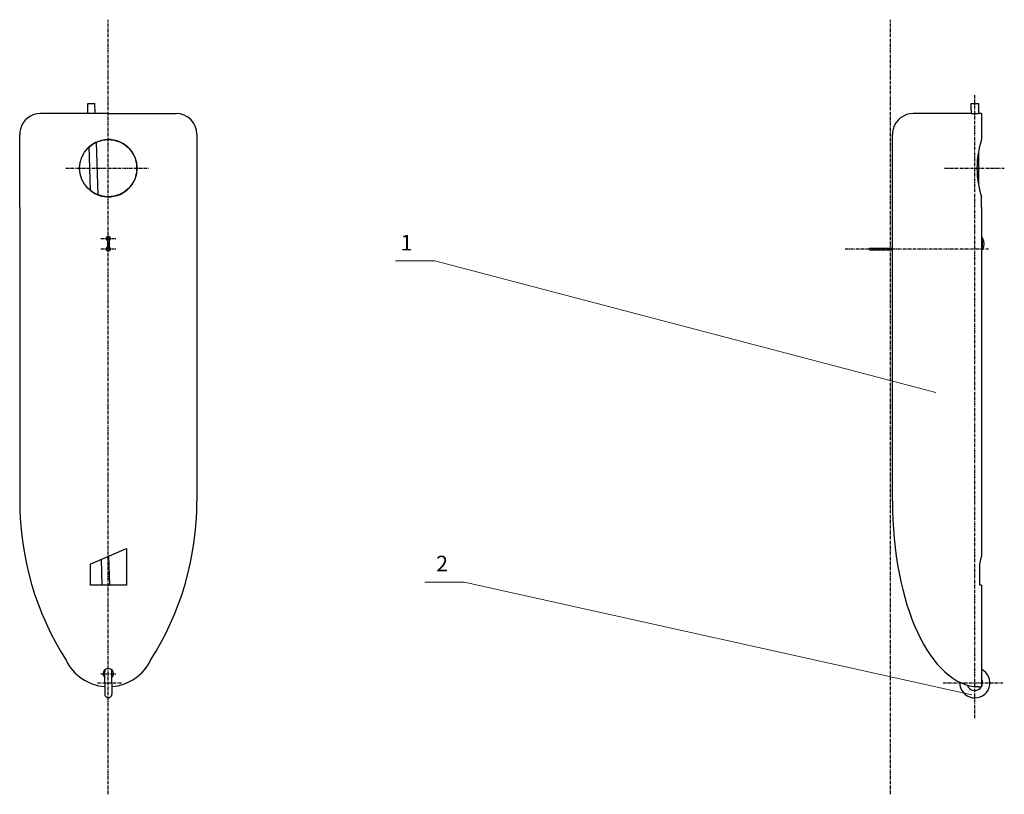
# Model space of a CAD drawing. Units: millimetres. Extents: x -17 to 172, y 40 to 189.
import ezdxf

# ---------------------------------------------------------------- set-up
doc = ezdxf.new("R2010")
doc.units = ezdxf.units.MM
doc.header["$LTSCALE"] = 0.2
doc.linetypes.add('ACAD_ISO10W100', pattern=[18, 12, -3, 0, -3])

msp = doc.modelspace()

# ---------------------------------------------------------------- linework, layer by layer
at = {"color": 1, "linetype": 'ACAD_ISO10W100', "lineweight": 25, "ltscale": 0.25}
for p, q in [((0, 114.83), (0, 189.15)), ((150, 114.83), (150, 189.15)), ((166.2, 55.09), (166.2, 174.77)), ((-8.12, 160.65), (7.88, 160.65)), ((160.36, 160.65), (171.86, 160.65)), ((-1.42, 147.15), (1.52, 147.15)), ((-1.42, 145.15), (1.52, 145.15)), ((141.36, 145.15), (168.85, 145.15)), ((0, 40.5), (0, 114.83)), ((150, 40.5), (150, 114.83)), ((-1.42, 63.65), (1.52, 63.65)), ((-2.08, 61.9), (2.53, 61.9)), ((160.1, 61.9), (171.6, 61.9))]:
    msp.add_line(p, q, dxfattribs=at)
at = {"color": 7, "lineweight": 30, "ltscale": 0.25}
for p, q in [((-3.9, 171.15), (-3.96, 173.05)), ((-3.96, 173.05), (-2.56, 173.05)), ((-2.5, 171.15), (-2.56, 173.05)), ((165.5, 173.05), (166.9, 173.05)), ((165.5, 171.85), (165.5, 173.05)), ((166.9, 173.05), (166.9, 171.15)), ((0, 171.15), (-13, 171.15)), ((0, 171.15), (13, 171.15)), ((165.5, 171.15), (154.4, 171.15)), ((165.5, 171.85), (165.5, 171.15)), ((165.5, 171.15), (166.9, 171.15)), ((167.5, 171.15), (166.9, 171.15)), ((167.5, 171.15), (167.5, 168.15)), ((167.5, 168.15), (167.5, 166.15)), ((-17, 153.15), (-17, 167.15)), ((17, 167.15), (17, 96.76)), ((150.4, 153.15), (150.4, 167.15)), ((-3.71, 164.89), (-3.46, 156.38)), ((-2.33, 165.63), (-2.03, 155.54)), ((166.9, 163.81), (166.9, 157.5)), ((167.5, 153.15), (167.5, 155.15)), ((-17, 153.15), (-17, 96.76)), ((150.4, 96.78), (150.4, 153.15)), ((167.5, 153.15), (167.5, 86.15)), ((-0.15, 147.15), (-0.15, 145.15)), ((0.15, 147.15), (0.15, 145.15)), ((146, 145.3), (150.4, 145.3)), ((146, 145.3), (146, 145)), ((146, 145), (150.4, 145)), ((-3.5, 84.65), (3.5, 87.65)), ((3.5, 87.65), (3.5, 80.65)), ((-1.19, 80.65), (-1.34, 85.58)), ((0.04, 86.17), (0.21, 80.65)), ((167.14, 84.65), (167.5, 86.15)), ((-3.5, 84.65), (-3.5, 80.65)), ((167.14, 80.65), (167.14, 84.65)), ((3.5, 80.65), (-3.5, 80.65)), ((167.5, 80.65), (167.14, 80.65)), ((167.5, 80.65), (167.5, 61.15)), ((-0.7, 61.9), (-0.7, 64.11)), ((0.7, 61.9), (0.7, 64.1)), ((-0.7, 61.9), (-0.7, 59.75)), ((0.7, 61.9), (0.7, 59.75)), ((166.9, 61.15), (167.5, 61.15))]:
    msp.add_line(p, q, dxfattribs=at)
at = {"color": 7, "lineweight": 15, "ltscale": 0.25}
for p, q in [((62.6, 142.89), (55.06, 142.89)), ((158.7, 117.64), (62.6, 142.89)), ((68.27, 81.22), (60.72, 81.22)), ((165.63, 59.56), (68.27, 81.22))]:
    msp.add_line(p, q, dxfattribs=at)
at = {"color": 7, "lineweight": 30, "ltscale": 0.25}
msp.add_circle((0, 160.65), 5.5, dxfattribs=at)
for centre, radius, start, end in [((-13, 167.15), 4, 90, 165.5225), ((13, 167.15), 4, 0, 90), ((154.4, 167.15), 4, 90, 165.5225), ((-13, 167.15), 4, 165.5225, 180), ((154.4, 167.15), 4, 165.5225, 180), ((0, 160.65), 5.5, 27.7254, 129.5212), ((184.11, 160.65), 17.5, 161.6823, 198.3177), ((0, 160.65), 5.5, 342.6983, 17.3017), ((0, 160.65), 5.5, 230.4788, 332.2746), ((0, 147.15), 0.4, 292.0243, 247.9757), ((0, 145.15), 0.4, 112.0243, 67.9757), ((0, 147.15), 0.15, 0, 180), ((167.5, 147), 0.3, 30, 90), ((165.8, 146.15), 1.9, 333.4587, 26.5413), ((165.8, 146.15), 2.2, 332.9877, 27.0123), ((0, 145.15), 0.15, 180, 0), ((167.5, 145.3), 0.3, 270, 330), ((39.81, 96.76), 56.81, 180, 212.5162), ((-39.81, 96.76), 56.81, 327.4838, 0), ((0, 70.15), 9, 205.928, 265.5392), ((0, 70.15), 9, 274.4608, 334.072), ((0, 63.65), 1, 314.427, 225.573), ((0, 64.1), 0.7, 150.7845, 180), ((0, 64.1), 0.7, 0, 29.2155), ((166.2, 61.9), 2.9, 177.882, 63.3881), ((166.2, 61.9), 1.5, 197.4351, 30), ((0, 59.75), 0.7, 180, 0)]:
    msp.add_arc(centre, radius, start, end, dxfattribs=at)
msp.add_ellipse((167, 96.76), major_axis=(-0.1, -35.6), ratio=0.466244, start_param=4.713084, end_param=6.283185, dxfattribs=at)

# ---------------------------------------------------------------- texts
at = {"color": 7, "lineweight": 15, "ltscale": 0.25}
for s, p in [('1', (56.06, 144.86)), ('2', (62.88, 83.28))]:
    msp.add_text(s, height=3, dxfattribs=at).set_placement(p)

doc.saveas('drawing.dxf')
